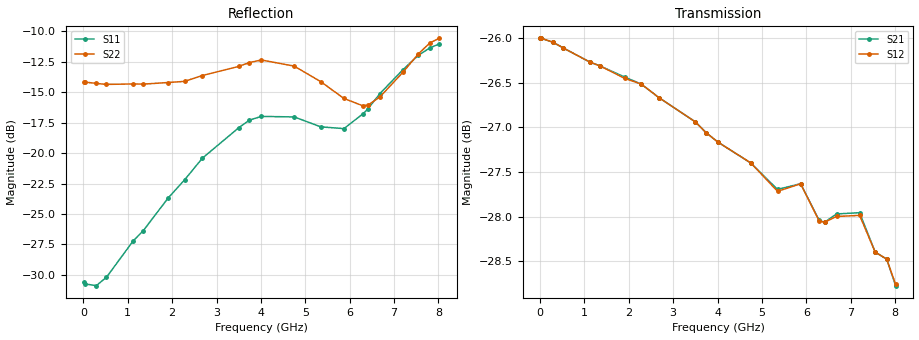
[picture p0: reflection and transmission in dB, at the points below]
! DEVICE ID: PE43712
! File Path: z:\PE43713\PE43713_CHAR_NOM_04292014\AMB\3p300\LS_ATT_24p75dB\PE43713_AMB_3p300V_3p000V_0p000V_LS_ATT_24p75dB_S2P_SN_10_A0139A.s2p
! Serial: 10
! Lot: A0139A
! Temp: 25C
! VDD: 3.300
! VSS: 0.000
! Control_Hi: 3.000
! Control_Lo: 0.000
! Attenuation Step: 24.75dB
! Port 1: RF1
! Port 2: RF2
! ThroughPath:1-2
! IDD: 0.0001452522
! ISS: -6.23e-008
#  Hz  S  RI  R  50
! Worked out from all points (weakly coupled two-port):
!   801 points, 10 MHz to 8.01 GHz, reference 50 ohm
!   highest |S21| = -26.01 dB at 30 MHz (marker M1); lowest = -28.8 dB at 8.01 GHz (marker M2)
!   lowest |S11| = -30.9 dB at 290 MHz (marker M3), VSWR 1.06, Z = 47.4 + j1.03 ohm
!   |S11| at or under -10 dB: start of sweep to end of sweep
!   |S22| runs from -16.1 to -10.6 dB; largest |S21 - S12| = 0.00019
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1e7  -0.0295 0.000806  0.0501 -0.000232  0.0501 -0.000236  -0.1961 0.00134
3e7  -0.029 0.00194  0.0501 -0.00057  0.0501 -0.000574  -0.1955 0.00323
2.9e8  -0.0264 0.0109  0.0496 -0.00505  0.0496 -0.00505  -0.1919 0.0214
5.2e8  -0.0244 0.019  0.0487 -0.00882  0.0487 -0.00881  -0.1877 0.0367
1.12e9  -0.0179 0.0397  0.0453 -0.0176  0.0453 -0.0176  -0.1756 0.0778
1.35e9  -0.0132 0.0462  0.0437 -0.0207  0.0437 -0.0207  -0.1686 0.0914
1.91e9  0.000827 0.0654  0.039 -0.0274  0.0389 -0.0274  -0.1461 0.1287
2.28e9  0.0131 0.0765  0.0352 -0.0315  0.0352 -0.0315  -0.1283 0.1492
2.68e9  0.0267 0.0914  0.0306 -0.0349  0.0306 -0.0349  -0.1065 0.1787
3.5e9  0.0457 0.1185  0.0204 -0.0401  0.0204 -0.0401  -0.0731 0.2146
3.74e9  0.0496 0.1271  0.0172 -0.0409  0.0172 -0.0409  -0.0676 0.2252
4.01e9  0.0534 0.1309  0.0138 -0.0416  0.0138 -0.0416  -0.063 0.2325
4.75e9  0.0635 0.1255  0.00473 -0.0424  0.0048 -0.0424  -0.0383 0.2241
5.35e9  0.0802 0.0998  -0.00183 -0.0412  -0.0018 -0.0411  -0.015 0.1956
5.87e9  0.1046 0.0702  -0.00784 -0.0408  -0.00779 -0.0408  0.0294 0.1649
6.29e9  0.1345 0.0526  -0.0125 -0.0376  -0.0124 -0.0376  0.0787 0.1352
6.41e9  0.1433 0.0497  -0.0131 -0.0373  -0.0131 -0.0373  0.0934 0.1264
6.68e9  0.1698 0.0437  -0.0158 -0.0367  -0.0157 -0.0366  0.1283 0.1113
7.2e9  0.2162 0.0397  -0.0222 -0.0333  -0.0221 -0.0332  0.1891 0.1013
7.55e9  0.2483 0.0434  -0.0245 -0.0291  -0.0245 -0.0291  0.2335 0.1041
7.81e9  0.2659 0.0482  -0.0261 -0.0272  -0.0261 -0.0272  0.2617 0.1084
8.01e9  0.275 0.0522  -0.0264 -0.0251  -0.0264 -0.0252  0.2751 0.1078
